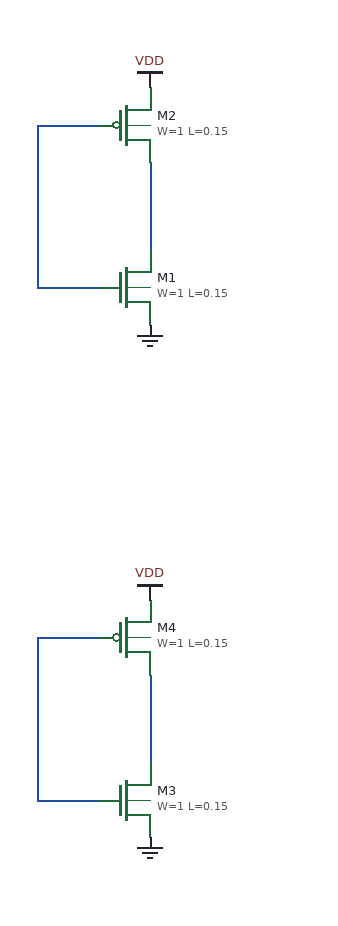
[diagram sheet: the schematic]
v {xschem version=3.4.8RC file_version=1.3}
G {}
K {}
V {}
S {}
F {}
E {}
N 550 -820 550 -750 {lab=#net1}
N 460 -850 510 -850 {lab=#net2}
N 460 -850 460 -720 {lab=#net2}
N 460 -720 510 -720 {lab=#net2}
N 550 -410 550 -340 {lab=#net1}
N 460 -440 510 -440 {lab=#net2}
N 460 -440 460 -310 {lab=#net2}
N 460 -310 510 -310 {lab=#net2}
C {sky130_fd_pr/nfet3_01v8.sym} 530 -720 0 0 {name=M1
W=1
L=0.15
body=GND
nf=1
mult=1
ad="expr('int((@nf + 1)/2) * @W / @nf * 0.29')"
pd="expr('2*int((@nf + 1)/2) * (@W / @nf + 0.29)')"
as="expr('int((@nf + 2)/2) * @W / @nf * 0.29')"
ps="expr('2*int((@nf + 2)/2) * (@W / @nf + 0.29)')"
nrd="expr('0.29 / @W ')" nrs="expr('0.29 / @W ')"
sa=0 sb=0 sd=0
model=nfet_01v8
spiceprefix=X
}
C {sky130_fd_pr/pfet3_01v8.sym} 530 -850 0 0 {name=M2
W=1
L=0.15
body=VDD
nf=1
mult=1
ad="expr('int((@nf + 1)/2) * @W / @nf * 0.29')"
pd="expr('2*int((@nf + 1)/2) * (@W / @nf + 0.29)')"
as="expr('int((@nf + 2)/2) * @W / @nf * 0.29')"
ps="expr('2*int((@nf + 2)/2) * (@W / @nf + 0.29)')"
nrd="expr('0.29 / @W ')" nrs="expr('0.29 / @W ')"
sa=0 sb=0 sd=0
model=pfet_01v8
spiceprefix=X
}
C {vdd.sym} 550 -880 0 0 {name=l1 lab=VDD}
C {gnd.sym} 550 -690 0 0 {name=l2 lab=GND}
C {sky130_fd_pr/nfet3_01v8.sym} 530 -310 0 0 {name=M3
W=1
L=0.15
body=GND
nf=1
mult=1
ad="expr('int((@nf + 1)/2) * @W / @nf * 0.29')"
pd="expr('2*int((@nf + 1)/2) * (@W / @nf + 0.29)')"
as="expr('int((@nf + 2)/2) * @W / @nf * 0.29')"
ps="expr('2*int((@nf + 2)/2) * (@W / @nf + 0.29)')"
nrd="expr('0.29 / @W ')" nrs="expr('0.29 / @W ')"
sa=0 sb=0 sd=0
model=nfet_01v8
spiceprefix=X
}
C {sky130_fd_pr/pfet3_01v8.sym} 530 -440 0 0 {name=M4
W=1
L=0.15
body=VDD
nf=1
mult=1
ad="expr('int((@nf + 1)/2) * @W / @nf * 0.29')"
pd="expr('2*int((@nf + 1)/2) * (@W / @nf + 0.29)')"
as="expr('int((@nf + 2)/2) * @W / @nf * 0.29')"
ps="expr('2*int((@nf + 2)/2) * (@W / @nf + 0.29)')"
nrd="expr('0.29 / @W ')" nrs="expr('0.29 / @W ')"
sa=0 sb=0 sd=0
model=pfet_01v8
spiceprefix=X
}
C {vdd.sym} 550 -470 0 0 {name=l3 lab=VDD}
C {gnd.sym} 550 -280 0 0 {name=l4 lab=GND}
